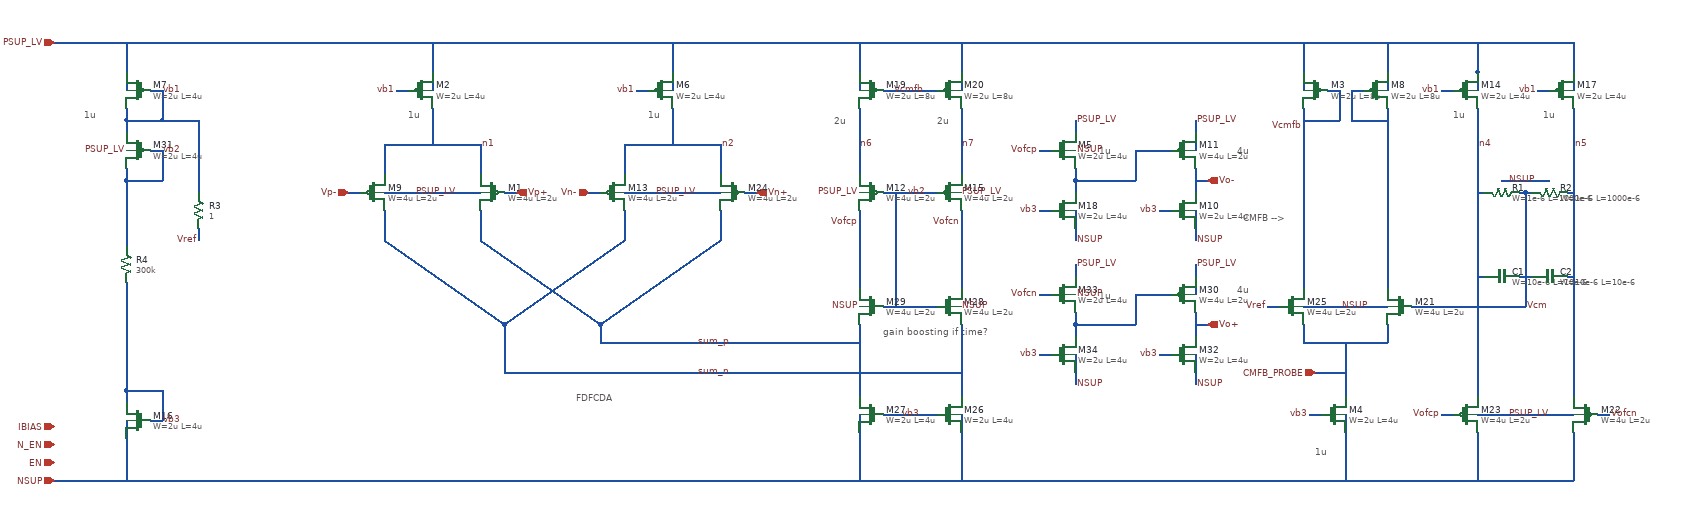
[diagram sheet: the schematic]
v {xschem version=3.4.7 file_version=1.2}
G {}
K {}
V {}
S {}
E {}
T {1u} -620 -620 0 0 0.4 0.4 {}
T {1u} -80 -620 0 0 0.4 0.4 {}
T {1u} 320 -620 0 0 0.4 0.4 {}
T {CMFB -->} 1310 -450 0 0 0.4 0.4 {}
T {2u} 630 -610 0 0 0.4 0.4 {}
T {2u} 800 -610 0 0 0.4 0.4 {}
T {gain boosting if time?
} 710 -260 0 0 0.2 0.2 {}
T {1u} 1430 -60 0 0 0.4 0.4 {}
T {FDFCDA} 200 -150 0 0 0.4 0.4 {}
T {1u} 1660 -620 0 0 0.4 0.4 {}
T {1u} 1810 -620 0 0 0.4 0.4 {}
T {4u} 1300 -560 0 0 0.4 0.4 {}
T {4u} 1300 -330 0 0 0.4 0.4 {}
T {1u} 1070 -560 0 0 0.4 0.4 {}
T {1u} 1070 -320 0 0 0.4 0.4 {}
N -660 -730 -260 -730 {lab=PSUP_LV}
N -670 -730 -660 -730 {lab=PSUP_LV}
N -550 -680 -550 -650 {lab=PSUP_LV}
N -550 -730 -550 -680 {lab=PSUP_LV}
N -550 -600 -490 -600 {lab=vb1}
N -490 -150 -490 -100 {lab=vb3}
N -550 -150 -550 -130 {lab=vb3}
N -510 -100 -490 -100 {lab=vb3}
N -670 0 -230 0 {lab=NSUP}
N -550 -80 -550 0 {lab=NSUP}
N -120 -560 -120 -510 {lab=n1}
N 40 -560 40 -510 {lab=n1}
N -230 0 -40 0 {lab=NSUP}
N -40 -620 -40 -560 {lab=n1}
N -40 -730 -40 -680 {lab=PSUP_LV}
N -120 -450 -120 -400 {lab=sum_n}
N -40 0 340 0 {lab=NSUP}
N 360 -680 360 -650 {lab=PSUP_LV}
N -100 -650 -80 -650 {lab=vb1}
N 300 -650 320 -650 {lab=vb1}
N 80 -480 100 -480 {lab=Vp+}
N -180 -480 -160 -480 {lab=Vp-}
N 1350 -290 1370 -290 {lab=Vref}
N 360 -730 360 -680 {lab=PSUP_LV}
N -40 -680 -40 -650 {lab=PSUP_LV}
N -120 -560 30 -560 {lab=n1}
N 280 -560 280 -510 {lab=n2}
N 440 -560 440 -510 {lab=n2}
N 280 -560 440 -560 {lab=n2}
N 360 -620 360 -560 {lab=n2}
N 40 -450 40 -400 {lab=sum_p}
N 440 -450 440 -400 {lab=sum_p}
N 980 0 1550 0 {lab=NSUP}
N 220 -480 240 -480 {lab=Vn-}
N 480 -480 500 -480 {lab=Vn+}
N 30 -560 40 -560 {lab=n1}
N -120 -400 80 -260 {lab=sum_n}
N 80 -260 280 -400 {lab=sum_n}
N 280 -480 430 -480 {lab=PSUP_LV}
N 280 -450 280 -400 {lab=sum_n}
N 40 -400 240 -260 {lab=sum_p}
N 240 -260 440 -400 {lab=sum_p}
N 430 -480 440 -480 {lab=PSUP_LV}
N -510 -650 -490 -650 {lab=vb1}
N 340 0 730 0 {lab=NSUP}
N 710 -650 800 -650 {lab=Vcmfb}
N 670 -110 670 0 {lab=NSUP}
N 840 -110 840 0 {lab=NSUP}
N 710 -110 800 -110 {lab=vb3}
N 670 -450 670 -320 {lab=Vofcp}
N 670 -620 670 -510 {lab=n6}
N 670 -730 670 -650 {lab=PSUP_LV}
N 840 -730 840 -650 {lab=PSUP_LV}
N 840 -620 840 -510 {lab=n7}
N 840 -450 840 -320 {lab=Vofcn}
N 670 -260 670 -140 {lab=sum_p}
N 840 -260 840 -140 {lab=sum_n}
N -490 -650 -490 -600 {lab=vb1}
N -550 -620 -550 -600 {lab=vb1}
N -550 -500 -490 -500 {lab=vb2}
N -490 -550 -490 -500 {lab=vb2}
N -550 -520 -550 -500 {lab=vb2}
N -510 -550 -490 -550 {lab=vb2}
N -550 -600 -550 -580 {lab=vb1}
N -550 -500 -550 -450 {lab=vb2}
N 740 -290 760 -290 {lab=vb2}
N 710 -290 740 -290 {lab=vb2}
N 760 -290 800 -290 {lab=vb2}
N 740 -480 760 -480 {lab=vb2}
N 710 -480 740 -480 {lab=vb2}
N 760 -480 800 -480 {lab=vb2}
N 80 -260 80 -210 {lab=sum_n}
N -550 -100 -550 -80 {lab=NSUP}
N -10 -730 1480 -730 {lab=PSUP_LV}
N 80 -180 780 -180 {lab=sum_n}
N 240 -230 610 -230 {lab=sum_p}
N 1410 -260 1410 -230 {lab=CMFB_PROBE}
N 1550 -260 1550 -230 {lab=CMFB_PROBE}
N 1410 -440 1410 -350 {lab=Vcmfb
}
N 1550 -400 1550 -350 {lab=#net1}
N 1550 -460 1550 -400 {lab=#net1}
N 1480 -80 1480 -20 {lab=NSUP}
N 1480 -20 1480 0 {lab=NSUP}
N 1480 -110 1480 -80 {lab=NSUP}
N 1550 -330 1550 -320 {lab=#net1}
N 1410 -330 1410 -320 {lab=Vcmfb}
N 1420 -290 1540 -290 {lab=NSUP}
N 1420 -230 1540 -230 {lab=CMFB_PROBE}
N 1450 -650 1460 -650 {lab=Vcmfb}
N 1410 -600 1460 -600 {lab=Vcmfb}
N 1500 -650 1510 -650 {lab=#net1}
N 1500 -600 1550 -600 {lab=#net1}
N 1460 -650 1470 -650 {lab=Vcmfb}
N 1470 -650 1470 -600 {lab=Vcmfb}
N 1460 -600 1470 -600 {lab=Vcmfb}
N 1490 -650 1500 -650 {lab=#net1}
N 1490 -650 1490 -600 {lab=#net1}
N 1490 -600 1500 -600 {lab=#net1}
N 1410 -290 1420 -290 {lab=NSUP}
N 1540 -290 1550 -290 {lab=NSUP}
N 1410 -230 1420 -230 {lab=CMFB_PROBE}
N 1540 -230 1550 -230 {lab=CMFB_PROBE}
N 1550 -610 1550 -460 {lab=#net1}
N 1410 -610 1410 -470 {lab=Vcmfb}
N 1410 -470 1410 -440 {lab=Vcmfb}
N 1550 -730 1550 -650 {lab=PSUP_LV}
N 1410 -730 1410 -650 {lab=PSUP_LV}
N 1410 -620 1410 -610 {lab=Vcmfb}
N 1550 -620 1550 -610 {lab=#net1}
N 1420 -110 1440 -110 {lab=vb3}
N 1410 -350 1410 -330 {lab=Vcmfb}
N 1550 -350 1550 -330 {lab=#net1}
N 1480 -230 1480 -140 {lab=CMFB_PROBE}
N 1640 -110 1660 -110 {lab=Vofcp}
N 1640 -110 1660 -110 {lab=Vofcp}
N 1900 -110 1920 -110 {lab=Vofcn}
N 1700 -620 1700 -140 {lab=n4}
N 1700 -80 1700 0 {lab=NSUP}
N 1700 -730 1700 -680 {lab=PSUP_LV}
N 1860 -620 1860 -140 {lab=n5}
N 1860 -80 1860 0 {lab=NSUP}
N 1860 -730 1860 -680 {lab=PSUP_LV}
N 1710 -110 1850 -110 {lab=PSUP_LV}
N 1780 -480 1790 -480 {lab=Vcm}
N 1770 -480 1780 -480 {lab=Vcm}
N 1780 -480 1780 -460 {lab=Vcm}
N 1740 -500 1780 -500 {lab=NSUP}
N 1780 -500 1820 -500 {lab=NSUP}
N 1700 -110 1710 -110 {lab=PSUP_LV}
N 1850 -110 1860 -110 {lab=PSUP_LV}
N 1700 -480 1710 -480 {lab=n4}
N 1850 -480 1860 -480 {lab=n5}
N 1700 -680 1700 -650 {lab=PSUP_LV}
N 1860 -680 1860 -650 {lab=PSUP_LV}
N 1800 -650 1820 -650 {lab=vb1}
N 1800 -650 1820 -650 {lab=vb1}
N 1550 0 1860 0 {lab=NSUP}
N 1590 -290 1780 -290 {lab=Vcm}
N 1780 -460 1780 -290 {lab=Vcm}
N 1480 -730 1860 -730 {lab=PSUP_LV}
N -430 -420 -430 -400 {lab=Vref}
N -430 -520 -430 -480 {lab=vb1}
N -430 -600 -430 -520 {lab=vb1}
N -490 -600 -430 -600 {lab=vb1}
N 730 0 980 0 {lab=NSUP}
N -260 -730 -10 -730 {lab=PSUP_LV}
N 1430 -180 1480 -180 {lab=CMFB_PROBE}
N 1700 -340 1710 -340 {lab=n4}
N 1770 -340 1780 -340 {lab=Vcm}
N 1780 -340 1790 -340 {lab=Vcm}
N 1850 -340 1860 -340 {lab=n5}
N -120 -480 40 -480 {lab=PSUP_LV}
N 780 -180 840 -180 {lab=sum_n}
N 610 -230 670 -230 {lab=sum_p}
N -550 -240 -550 -150 {lab=vb3}
N -550 -150 -490 -150 {lab=vb3}
N 730 -480 730 -290 {lab=vb2}
N -550 -450 -550 -390 {lab=vb2}
N -550 -330 -550 -240 {lab=vb3}
N 1230 -520 1230 -480 {lab=Vo-}
N 1230 -500 1250 -500 {lab=Vo-}
N 1230 -600 1230 -580 {lab=PSUP_LV}
N 1230 -420 1230 -400 {lab=NSUP}
N 1230 -280 1230 -240 {lab=Vo+}
N 1230 -260 1250 -260 {lab=Vo+}
N 1230 -360 1230 -340 {lab=PSUP_LV}
N 1230 -180 1230 -160 {lab=NSUP}
N 80 -210 80 -180 {lab=sum_n}
N 240 -260 240 -230 {lab=sum_p}
N 1170 -210 1190 -210 {lab=vb3}
N 1170 -450 1190 -450 {lab=vb3}
N 1230 -450 1230 -420 {lab=NSUP}
N 1230 -210 1230 -180 {lab=NSUP}
N 1230 -580 1230 -550 {lab=PSUP_LV}
N 1230 -340 1230 -310 {lab=PSUP_LV}
N 1170 -310 1190 -310 {lab=#net2}
N 1180 -550 1190 -550 {lab=#net3}
N 1640 -650 1660 -650 {lab=vb1}
N 1640 -650 1660 -650 {lab=vb1}
N 1700 -680 1700 -650 {lab=PSUP_LV}
N 1030 -500 1050 -500 {lab=#net3}
N 1030 -600 1030 -580 {lab=PSUP_LV}
N 1030 -420 1030 -400 {lab=NSUP}
N 1030 -500 1030 -480 {lab=#net3}
N 1030 -520 1030 -500 {lab=#net3}
N 1030 -450 1030 -420 {lab=NSUP}
N 1030 -260 1050 -260 {lab=#net2}
N 1030 -360 1030 -340 {lab=PSUP_LV}
N 1030 -180 1030 -160 {lab=NSUP}
N 1030 -260 1030 -240 {lab=#net2}
N 1030 -280 1030 -260 {lab=#net2}
N 1030 -210 1030 -180 {lab=NSUP}
N 970 -210 990 -210 {lab=vb3}
N 970 -450 990 -450 {lab=vb3}
N 1050 -260 1130 -260 {lab=#net2}
N 1130 -310 1130 -260 {lab=#net2}
N 1130 -310 1170 -310 {lab=#net2}
N 970 -550 990 -550 {lab=Vofcp}
N 1130 -550 1180 -550 {lab=#net3}
N 1130 -550 1130 -500 {lab=#net3}
N 1050 -500 1130 -500 {lab=#net3}
N 970 -310 990 -310 {lab=Vofcn}
C {noconn.sym} -670 -60 0 1 {name=l1}
C {noconn.sym} -670 -30 0 1 {name=l2}
C {ipin.sym} -670 -730 0 0 {name=p19 lab=PSUP_LV
}
C {ipin.sym} -670 0 0 0 {name=p20 lab=NSUP
}
C {ipin.sym} -670 -60 0 0 {name=p21 lab=N_EN

}
C {ipin.sym} -670 -30 0 0 {name=p22 lab=EN
}
C {ipin.sym} -670 -90 0 0 {name=p9 lab=IBIAS


}
C {symbols/pfet_03v3.sym} -530 -650 0 1 {name=M7
L=4u
W=2u
nf=1
m=4
ad="'int((nf+1)/2) * W/nf * 0.18u'"
pd="'2*int((nf+1)/2) * (W/nf + 0.18u)'"
as="'int((nf+2)/2) * W/nf * 0.18u'"
ps="'2*int((nf+2)/2) * (W/nf + 0.18u)'"
nrd="'0.18u / W'" nrs="'0.18u / W'"
sa=0 sb=0 sd=0
model=pfet_03v3
spiceprefix=X
}
C {lab_pin.sym} -490 -650 0 1 {name=p8 sig_type=std_logic lab=vb1}
C {noconn.sym} -670 -90 0 1 {name=l3}
C {symbols/nfet_03v3.sym} -530 -100 0 1 {name=M16
L=4u
W=2u
nf=1
m=4
ad="'int((nf+1)/2) * W/nf * 0.18u'"
pd="'2*int((nf+1)/2) * (W/nf + 0.18u)'"
as="'int((nf+2)/2) * W/nf * 0.18u'"
ps="'2*int((nf+2)/2) * (W/nf + 0.18u)'"
nrd="'0.18u / W'" nrs="'0.18u / W'"
sa=0 sb=0 sd=0
model=nfet_03v3
spiceprefix=X
}
C {lab_pin.sym} -490 -100 2 0 {name=p29 sig_type=std_logic lab=vb3}
C {symbols/pfet_03v3.sym} -140 -480 0 0 {name=M9
L=2u
W=4u
nf=5
m=10
ad="'int((nf+1)/2) * W/nf * 0.18u'"
pd="'2*int((nf+1)/2) * (W/nf + 0.18u)'"
as="'int((nf+2)/2) * W/nf * 0.18u'"
ps="'2*int((nf+2)/2) * (W/nf + 0.18u)'"
nrd="'0.18u / W'" nrs="'0.18u / W'"
sa=0 sb=0 sd=0
model=pfet_03v3
spiceprefix=X
}
C {symbols/pfet_03v3.sym} 60 -480 0 1 {name=M1
L=2u
W=4u
nf=5
m=10
ad="'int((nf+1)/2) * W/nf * 0.18u'"
pd="'2*int((nf+1)/2) * (W/nf + 0.18u)'"
as="'int((nf+2)/2) * W/nf * 0.18u'"
ps="'2*int((nf+2)/2) * (W/nf + 0.18u)'"
nrd="'0.18u / W'" nrs="'0.18u / W'"
sa=0 sb=0 sd=0
model=pfet_03v3
spiceprefix=X
}
C {lab_pin.sym} -70 -480 2 0 {name=p6 sig_type=std_logic lab=PSUP_LV}
C {symbols/pfet_03v3.sym} -60 -650 0 0 {name=M2
L=4u
W=2u
nf=1
m=4
ad="'int((nf+1)/2) * W/nf * 0.18u'"
pd="'2*int((nf+1)/2) * (W/nf + 0.18u)'"
as="'int((nf+2)/2) * W/nf * 0.18u'"
ps="'2*int((nf+2)/2) * (W/nf + 0.18u)'"
nrd="'0.18u / W'" nrs="'0.18u / W'"
sa=0 sb=0 sd=0
model=pfet_03v3
spiceprefix=X
}
C {symbols/pfet_03v3.sym} 340 -650 0 0 {name=M6
L=4u
W=2u
nf=1
m=4
ad="'int((nf+1)/2) * W/nf * 0.18u'"
pd="'2*int((nf+1)/2) * (W/nf + 0.18u)'"
as="'int((nf+2)/2) * W/nf * 0.18u'"
ps="'2*int((nf+2)/2) * (W/nf + 0.18u)'"
nrd="'0.18u / W'" nrs="'0.18u / W'"
sa=0 sb=0 sd=0
model=pfet_03v3
spiceprefix=X
}
C {lab_pin.sym} -100 -650 0 0 {name=p16 sig_type=std_logic lab=vb1}
C {lab_pin.sym} 300 -650 0 0 {name=p17 sig_type=std_logic lab=vb1}
C {ipin.sym} 100 -480 0 1 {name=p23 lab=Vp+

}
C {ipin.sym} -180 -480 0 0 {name=p24 lab=Vp-

}
C {ipin.sym} 500 -480 0 1 {name=p25 lab=Vn+

}
C {ipin.sym} 220 -480 0 0 {name=p26 lab=Vn-

}
C {lab_pin.sym} 1350 -290 0 0 {name=p7 sig_type=std_logic lab=Vref}
C {lab_pin.sym} 40 -560 2 0 {name=p11 sig_type=std_logic lab=n1}
C {lab_pin.sym} 440 -560 2 0 {name=p14 sig_type=std_logic lab=n2}
C {symbols/pfet_03v3.sym} 460 -480 0 1 {name=M24
L=2u
W=4u
nf=5
m=10
ad="'int((nf+1)/2) * W/nf * 0.18u'"
pd="'2*int((nf+1)/2) * (W/nf + 0.18u)'"
as="'int((nf+2)/2) * W/nf * 0.18u'"
ps="'2*int((nf+2)/2) * (W/nf + 0.18u)'"
nrd="'0.18u / W'" nrs="'0.18u / W'"
sa=0 sb=0 sd=0
model=pfet_03v3
spiceprefix=X
}
C {lab_pin.sym} 330 -480 2 0 {name=p28 sig_type=std_logic lab=PSUP_LV}
C {symbols/pfet_03v3.sym} 260 -480 0 0 {name=M13
L=2u
W=4u
nf=5
m=10
ad="'int((nf+1)/2) * W/nf * 0.18u'"
pd="'2*int((nf+1)/2) * (W/nf + 0.18u)'"
as="'int((nf+2)/2) * W/nf * 0.18u'"
ps="'2*int((nf+2)/2) * (W/nf + 0.18u)'"
nrd="'0.18u / W'" nrs="'0.18u / W'"
sa=0 sb=0 sd=0
model=pfet_03v3
spiceprefix=X
}
C {symbols/pfet_03v3.sym} 690 -480 0 1 {name=M12
L=2u
W=4u
nf=5
m=8
ad="'int((nf+1)/2) * W/nf * 0.18u'"
pd="'2*int((nf+1)/2) * (W/nf + 0.18u)'"
as="'int((nf+2)/2) * W/nf * 0.18u'"
ps="'2*int((nf+2)/2) * (W/nf + 0.18u)'"
nrd="'0.18u / W'" nrs="'0.18u / W'"
sa=0 sb=0 sd=0
model=pfet_03v3
spiceprefix=X
}
C {symbols/pfet_03v3.sym} 820 -480 0 0 {name=M15
L=2u
W=4u
nf=5
m=8
ad="'int((nf+1)/2) * W/nf * 0.18u'"
pd="'2*int((nf+1)/2) * (W/nf + 0.18u)'"
as="'int((nf+2)/2) * W/nf * 0.18u'"
ps="'2*int((nf+2)/2) * (W/nf + 0.18u)'"
nrd="'0.18u / W'" nrs="'0.18u / W'"
sa=0 sb=0 sd=0
model=pfet_03v3
spiceprefix=X
}
C {lab_pin.sym} 670 -480 2 1 {name=p34 sig_type=std_logic lab=PSUP_LV}
C {symbols/pfet_03v3.sym} 690 -650 0 1 {name=M19
L=8u
W=2u
nf=1
m=8
ad="'int((nf+1)/2) * W/nf * 0.18u'"
pd="'2*int((nf+1)/2) * (W/nf + 0.18u)'"
as="'int((nf+2)/2) * W/nf * 0.18u'"
ps="'2*int((nf+2)/2) * (W/nf + 0.18u)'"
nrd="'0.18u / W'" nrs="'0.18u / W'"
sa=0 sb=0 sd=0
model=pfet_03v3
spiceprefix=X
}
C {symbols/pfet_03v3.sym} 820 -650 0 0 {name=M20
L=8u
W=2u
nf=1
m=8
ad="'int((nf+1)/2) * W/nf * 0.18u'"
pd="'2*int((nf+1)/2) * (W/nf + 0.18u)'"
as="'int((nf+2)/2) * W/nf * 0.18u'"
ps="'2*int((nf+2)/2) * (W/nf + 0.18u)'"
nrd="'0.18u / W'" nrs="'0.18u / W'"
sa=0 sb=0 sd=0
model=pfet_03v3
spiceprefix=X
}
C {lab_pin.sym} 840 -480 2 0 {name=p37 sig_type=std_logic lab=PSUP_LV}
C {symbols/nfet_03v3.sym} 820 -110 0 0 {name=M26
L=4u
W=2u
nf=1
m=8
ad="'int((nf+1)/2) * W/nf * 0.18u'"
pd="'2*int((nf+1)/2) * (W/nf + 0.18u)'"
as="'int((nf+2)/2) * W/nf * 0.18u'"
ps="'2*int((nf+2)/2) * (W/nf + 0.18u)'"
nrd="'0.18u / W'" nrs="'0.18u / W'"
sa=0 sb=0 sd=0
model=nfet_03v3
spiceprefix=X
}
C {lab_pin.sym} 780 -650 0 0 {name=p39 sig_type=std_logic lab=Vcmfb}
C {lab_pin.sym} 740 -110 2 0 {name=p38 sig_type=std_logic lab=vb3}
C {symbols/nfet_03v3.sym} 690 -110 0 1 {name=M27
L=4u
W=2u
nf=1
m=8
ad="'int((nf+1)/2) * W/nf * 0.18u'"
pd="'2*int((nf+1)/2) * (W/nf + 0.18u)'"
as="'int((nf+2)/2) * W/nf * 0.18u'"
ps="'2*int((nf+2)/2) * (W/nf + 0.18u)'"
nrd="'0.18u / W'" nrs="'0.18u / W'"
sa=0 sb=0 sd=0
model=nfet_03v3
spiceprefix=X
}
C {symbols/nfet_03v3.sym} 820 -290 0 0 {name=M28
L=2u
W=4u
nf=5
m=4
ad="'int((nf+1)/2) * W/nf * 0.18u'"
pd="'2*int((nf+1)/2) * (W/nf + 0.18u)'"
as="'int((nf+2)/2) * W/nf * 0.18u'"
ps="'2*int((nf+2)/2) * (W/nf + 0.18u)'"
nrd="'0.18u / W'" nrs="'0.18u / W'"
sa=0 sb=0 sd=0
model=nfet_03v3
spiceprefix=X
}
C {symbols/nfet_03v3.sym} 690 -290 0 1 {name=M29
L=2u
W=4u
nf=5
m=4
ad="'int((nf+1)/2) * W/nf * 0.18u'"
pd="'2*int((nf+1)/2) * (W/nf + 0.18u)'"
as="'int((nf+2)/2) * W/nf * 0.18u'"
ps="'2*int((nf+2)/2) * (W/nf + 0.18u)'"
nrd="'0.18u / W'" nrs="'0.18u / W'"
sa=0 sb=0 sd=0
model=nfet_03v3
spiceprefix=X
}
C {lab_pin.sym} 400 -230 2 0 {name=p41 sig_type=std_logic lab=sum_p}
C {lab_pin.sym} 400 -180 2 0 {name=p43 sig_type=std_logic lab=sum_n}
C {symbols/pfet_03v3.sym} -530 -550 0 1 {name=M31
L=4u
W=2u
nf=1
m=4
ad="'int((nf+1)/2) * W/nf * 0.18u'"
pd="'2*int((nf+1)/2) * (W/nf + 0.18u)'"
as="'int((nf+2)/2) * W/nf * 0.18u'"
ps="'2*int((nf+2)/2) * (W/nf + 0.18u)'"
nrd="'0.18u / W'" nrs="'0.18u / W'"
sa=0 sb=0 sd=0
model=pfet_03v3
spiceprefix=X
}
C {lab_pin.sym} 670 -290 2 1 {name=p50 sig_type=std_logic lab=NSUP}
C {lab_pin.sym} 840 -290 2 0 {name=p51 sig_type=std_logic lab=NSUP}
C {lab_pin.sym} -550 -550 2 1 {name=p18 sig_type=std_logic lab=PSUP_LV}
C {symbols/pfet_03v3.sym} 1430 -650 0 1 {name=M3
L=8u
W=2u
nf=1
m=2
ad="'int((nf+1)/2) * W/nf * 0.18u'"
pd="'2*int((nf+1)/2) * (W/nf + 0.18u)'"
as="'int((nf+2)/2) * W/nf * 0.18u'"
ps="'2*int((nf+2)/2) * (W/nf + 0.18u)'"
nrd="'0.18u / W'" nrs="'0.18u / W'"
sa=0 sb=0 sd=0
model=pfet_03v3
spiceprefix=X
}
C {symbols/pfet_03v3.sym} 1530 -650 0 0 {name=M8
L=8u
W=2u
nf=1
m=2
ad="'int((nf+1)/2) * W/nf * 0.18u'"
pd="'2*int((nf+1)/2) * (W/nf + 0.18u)'"
as="'int((nf+2)/2) * W/nf * 0.18u'"
ps="'2*int((nf+2)/2) * (W/nf + 0.18u)'"
nrd="'0.18u / W'" nrs="'0.18u / W'"
sa=0 sb=0 sd=0
model=pfet_03v3
spiceprefix=X
}
C {lab_pin.sym} 1520 -290 0 0 {name=p52 sig_type=std_logic lab=NSUP}
C {symbols/nfet_03v3.sym} 1570 -290 0 1 {name=M21
L=2u
W=4u
nf=5
m=4
ad="'int((nf+1)/2) * W/nf * 0.18u'"
pd="'2*int((nf+1)/2) * (W/nf + 0.18u)'"
as="'int((nf+2)/2) * W/nf * 0.18u'"
ps="'2*int((nf+2)/2) * (W/nf + 0.18u)'"
nrd="'0.18u / W'" nrs="'0.18u / W'"
sa=0 sb=0 sd=0
model=nfet_03v3
spiceprefix=X
}
C {symbols/nfet_03v3.sym} 1390 -290 0 0 {name=M25
L=2u
W=4u
nf=5
m=4
ad="'int((nf+1)/2) * W/nf * 0.18u'"
pd="'2*int((nf+1)/2) * (W/nf + 0.18u)'"
as="'int((nf+2)/2) * W/nf * 0.18u'"
ps="'2*int((nf+2)/2) * (W/nf + 0.18u)'"
nrd="'0.18u / W'" nrs="'0.18u / W'"
sa=0 sb=0 sd=0
model=nfet_03v3
spiceprefix=X
}
C {lab_pin.sym} 1410 -590 0 0 {name=p1 sig_type=std_logic lab=Vcmfb}
C {lab_pin.sym} 1420 -110 0 0 {name=p12 sig_type=std_logic lab=vb3}
C {symbols/nfet_03v3.sym} 1460 -110 0 0 {name=M4
L=4u
W=2u
nf=1
m=4
ad="'int((nf+1)/2) * W/nf * 0.18u'"
pd="'2*int((nf+1)/2) * (W/nf + 0.18u)'"
as="'int((nf+2)/2) * W/nf * 0.18u'"
ps="'2*int((nf+2)/2) * (W/nf + 0.18u)'"
nrd="'0.18u / W'" nrs="'0.18u / W'"
sa=0 sb=0 sd=0
model=nfet_03v3
spiceprefix=X
}
C {lab_pin.sym} 670 -560 2 0 {name=p35 sig_type=std_logic lab=n6}
C {lab_pin.sym} 840 -560 2 0 {name=p36 sig_type=std_logic lab=n7}
C {symbols/pfet_03v3.sym} 1880 -110 0 1 {name=M22
L=2u
W=4u
nf=5
m=4
ad="'int((nf+1)/2) * W/nf * 0.18u'"
pd="'2*int((nf+1)/2) * (W/nf + 0.18u)'"
as="'int((nf+2)/2) * W/nf * 0.18u'"
ps="'2*int((nf+2)/2) * (W/nf + 0.18u)'"
nrd="'0.18u / W'" nrs="'0.18u / W'"
sa=0 sb=0 sd=0
model=pfet_03v3
spiceprefix=X
}
C {symbols/pfet_03v3.sym} 1680 -110 0 0 {name=M23
L=2u
W=4u
nf=5
m=4
ad="'int((nf+1)/2) * W/nf * 0.18u'"
pd="'2*int((nf+1)/2) * (W/nf + 0.18u)'"
as="'int((nf+2)/2) * W/nf * 0.18u'"
ps="'2*int((nf+2)/2) * (W/nf + 0.18u)'"
nrd="'0.18u / W'" nrs="'0.18u / W'"
sa=0 sb=0 sd=0
model=pfet_03v3
spiceprefix=X
}
C {symbols/ppolyf_u_3k.sym} 1740 -480 1 0 {name=R1
W=1e-6
L=1000e-6
model=ppolyf_u_3k
spiceprefix=X
m=1}
C {symbols/ppolyf_u_3k.sym} 1820 -480 1 0 {name=R2
W=1e-6
L=1000e-6
model=ppolyf_u_3k
spiceprefix=X
m=1}
C {lab_pin.sym} 1780 -290 0 1 {name=p46 sig_type=std_logic lab=Vcm}
C {lab_pin.sym} 1750 -500 0 1 {name=p53 sig_type=std_logic lab=NSUP}
C {lab_pin.sym} 1700 -560 2 0 {name=p54 sig_type=std_logic lab=n4}
C {lab_pin.sym} 1860 -560 2 0 {name=p55 sig_type=std_logic lab=n5}
C {lab_pin.sym} 1750 -110 2 0 {name=p56 sig_type=std_logic lab=PSUP_LV}
C {symbols/pfet_03v3.sym} 1840 -650 0 0 {name=M17
L=4u
W=2u
nf=1
m=4
ad="'int((nf+1)/2) * W/nf * 0.18u'"
pd="'2*int((nf+1)/2) * (W/nf + 0.18u)'"
as="'int((nf+2)/2) * W/nf * 0.18u'"
ps="'2*int((nf+2)/2) * (W/nf + 0.18u)'"
nrd="'0.18u / W'" nrs="'0.18u / W'"
sa=0 sb=0 sd=0
model=pfet_03v3
spiceprefix=X
}
C {lab_pin.sym} 1800 -650 0 0 {name=p58 sig_type=std_logic lab=vb1}
C {lab_pin.sym} -430 -400 0 0 {name=p3 sig_type=std_logic lab=Vref}
C {res.sym} -430 -450 0 0 {name=R3
value=1
footprint=1206
device=resistor
m=1}
C {ipin.sym} 1430 -180 0 0 {name=p2 lab=CMFB_PROBE


}
C {gf180mcu_fd_pr/cap_mim_2f0fF.sym} 1740 -340 1 0 {name=C1
W=10e-6
L=10e-6
model=cap_mim_2f0fF
spiceprefix=X
m=1}
C {gf180mcu_fd_pr/cap_mim_2f0fF.sym} 1820 -340 1 0 {name=C2
W=10e-6
L=10e-6
model=cap_mim_2f0fF
spiceprefix=X
m=1}
C {lab_pin.sym} 750 -480 2 0 {name=p4 sig_type=std_logic lab=vb2}
C {lab_pin.sym} -490 -550 2 0 {name=p5 sig_type=std_logic lab=vb2}
C {res.sym} -550 -360 0 0 {name=R4
value=300k
footprint=1206
device=resistor
m=1}
C {lab_pin.sym} 670 -430 0 0 {name=p33 sig_type=std_logic lab=Vofcp}
C {lab_pin.sym} 840 -430 0 0 {name=p44 sig_type=std_logic lab=Vofcn}
C {lab_pin.sym} 1230 -600 2 0 {name=p10 sig_type=std_logic lab=PSUP_LV}
C {lab_pin.sym} 1230 -400 2 0 {name=p30 sig_type=std_logic lab=NSUP}
C {lab_pin.sym} 1230 -360 2 0 {name=p48 sig_type=std_logic lab=PSUP_LV}
C {lab_pin.sym} 1230 -160 2 0 {name=p49 sig_type=std_logic lab=NSUP}
C {opin.sym} 1250 -260 0 0 {name=p13 lab=Vo+}
C {opin.sym} 1250 -500 0 0 {name=p27 lab=Vo-}
C {lab_pin.sym} 1640 -110 0 0 {name=p40 sig_type=std_logic lab=Vofcp}
C {lab_pin.sym} 1920 -110 0 1 {name=p42 sig_type=std_logic lab=Vofcn}
C {symbols/pfet_06v0.sym} 1210 -310 0 0 {name=M30
L=2u
W=4u
nf=4
m=4
ad="'int((nf+1)/2) * W/nf * 0.18u'"
pd="'2*int((nf+1)/2) * (W/nf + 0.18u)'"
as="'int((nf+2)/2) * W/nf * 0.18u'"
ps="'2*int((nf+2)/2) * (W/nf + 0.18u)'"
nrd="'0.18u / W'" nrs="'0.18u / W'"
sa=0 sb=0 sd=0
model=pfet_06v0
spiceprefix=X
}
C {symbols/nfet_06v0_nvt.sym} 1210 -210 0 0 {name=M32
L=4u
W=2u
nf=4
m=16
ad="'int((nf+1)/2) * W/nf * 0.18u'"
pd="'2*int((nf+1)/2) * (W/nf + 0.18u)'"
as="'int((nf+2)/2) * W/nf * 0.18u'"
ps="'2*int((nf+2)/2) * (W/nf + 0.18u)'"
nrd="'0.18u / W'" nrs="'0.18u / W'"
sa=0 sb=0 sd=0
model=nfet_06v0
spiceprefix=X
}
C {lab_pin.sym} 1170 -210 2 1 {name=p15 sig_type=std_logic lab=vb3}
C {lab_pin.sym} 1170 -450 2 1 {name=p31 sig_type=std_logic lab=vb3}
C {symbols/nfet_06v0_nvt.sym} 1210 -450 0 0 {name=M10
L=4u
W=2u
nf=4
m=16
ad="'int((nf+1)/2) * W/nf * 0.18u'"
pd="'2*int((nf+1)/2) * (W/nf + 0.18u)'"
as="'int((nf+2)/2) * W/nf * 0.18u'"
ps="'2*int((nf+2)/2) * (W/nf + 0.18u)'"
nrd="'0.18u / W'" nrs="'0.18u / W'"
sa=0 sb=0 sd=0
model=nfet_06v0
spiceprefix=X
}
C {symbols/pfet_06v0.sym} 1210 -550 0 0 {name=M11
L=2u
W=4u
nf=4
m=4
ad="'int((nf+1)/2) * W/nf * 0.18u'"
pd="'2*int((nf+1)/2) * (W/nf + 0.18u)'"
as="'int((nf+2)/2) * W/nf * 0.18u'"
ps="'2*int((nf+2)/2) * (W/nf + 0.18u)'"
nrd="'0.18u / W'" nrs="'0.18u / W'"
sa=0 sb=0 sd=0
model=pfet_06v0
spiceprefix=X
}
C {symbols/pfet_03v3.sym} 1680 -650 0 0 {name=M14
L=4u
W=2u
nf=1
m=4
ad="'int((nf+1)/2) * W/nf * 0.18u'"
pd="'2*int((nf+1)/2) * (W/nf + 0.18u)'"
as="'int((nf+2)/2) * W/nf * 0.18u'"
ps="'2*int((nf+2)/2) * (W/nf + 0.18u)'"
nrd="'0.18u / W'" nrs="'0.18u / W'"
sa=0 sb=0 sd=0
model=pfet_03v3
spiceprefix=X
}
C {lab_pin.sym} 1030 -600 2 0 {name=p45 sig_type=std_logic lab=PSUP_LV}
C {lab_pin.sym} 1030 -400 2 0 {name=p47 sig_type=std_logic lab=NSUP}
C {lab_pin.sym} 1640 -650 0 0 {name=p32 sig_type=std_logic lab=vb1}
C {symbols/nfet_03v3.sym} 1010 -550 0 0 {name=M5
L=4u
W=2u
nf=1
m=8
ad="'int((nf+1)/2) * W/nf * 0.18u'"
pd="'2*int((nf+1)/2) * (W/nf + 0.18u)'"
as="'int((nf+2)/2) * W/nf * 0.18u'"
ps="'2*int((nf+2)/2) * (W/nf + 0.18u)'"
nrd="'0.18u / W'" nrs="'0.18u / W'"
sa=0 sb=0 sd=0
model=nfet_03v3
spiceprefix=X
}
C {lab_pin.sym} 1030 -550 2 0 {name=p60 sig_type=std_logic lab=NSUP}
C {symbols/nfet_03v3.sym} 1010 -450 0 0 {name=M18
L=4u
W=2u
nf=1
m=4
ad="'int((nf+1)/2) * W/nf * 0.18u'"
pd="'2*int((nf+1)/2) * (W/nf + 0.18u)'"
as="'int((nf+2)/2) * W/nf * 0.18u'"
ps="'2*int((nf+2)/2) * (W/nf + 0.18u)'"
nrd="'0.18u / W'" nrs="'0.18u / W'"
sa=0 sb=0 sd=0
model=nfet_03v3
spiceprefix=X
}
C {lab_pin.sym} 1030 -360 2 0 {name=p57 sig_type=std_logic lab=PSUP_LV}
C {lab_pin.sym} 1030 -160 2 0 {name=p59 sig_type=std_logic lab=NSUP}
C {symbols/nfet_03v3.sym} 1010 -310 0 0 {name=M33
L=4u
W=2u
nf=1
m=8
ad="'int((nf+1)/2) * W/nf * 0.18u'"
pd="'2*int((nf+1)/2) * (W/nf + 0.18u)'"
as="'int((nf+2)/2) * W/nf * 0.18u'"
ps="'2*int((nf+2)/2) * (W/nf + 0.18u)'"
nrd="'0.18u / W'" nrs="'0.18u / W'"
sa=0 sb=0 sd=0
model=nfet_03v3
spiceprefix=X
}
C {lab_pin.sym} 1030 -310 2 0 {name=p61 sig_type=std_logic lab=NSUP}
C {symbols/nfet_03v3.sym} 1010 -210 0 0 {name=M34
L=4u
W=2u
nf=1
m=4
ad="'int((nf+1)/2) * W/nf * 0.18u'"
pd="'2*int((nf+1)/2) * (W/nf + 0.18u)'"
as="'int((nf+2)/2) * W/nf * 0.18u'"
ps="'2*int((nf+2)/2) * (W/nf + 0.18u)'"
nrd="'0.18u / W'" nrs="'0.18u / W'"
sa=0 sb=0 sd=0
model=nfet_03v3
spiceprefix=X
}
C {lab_pin.sym} 970 -210 2 1 {name=p62 sig_type=std_logic lab=vb3}
C {lab_pin.sym} 970 -450 2 1 {name=p63 sig_type=std_logic lab=vb3}
C {lab_pin.sym} 970 -550 0 0 {name=p66 sig_type=std_logic lab=Vofcp}
C {lab_pin.sym} 970 -310 0 0 {name=p64 sig_type=std_logic lab=Vofcn}
